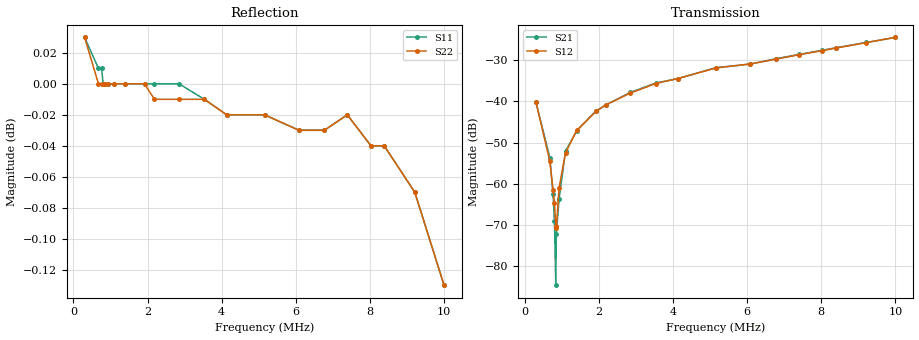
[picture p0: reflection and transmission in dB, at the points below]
!s-Parameter Generated by FASTRON Sdn. Bhd.
!FASTRON P/N : 1812AFTC-492X
!Keysight Technologies: E5071C_MY46733604_B.14.02
!Date: Wed Mar 18 14:02:51 2026
!Version  :Rev00  Wed Mar 18 14:02:51 2026
!Data & Calibration Information:
!Freq  S11:SOLT2(ON)  S21:SOLT2(ON)  S12:SOLT2(ON)  S22:SOLT2(ON)
!PortZ  Port1:50+j0  Port2:50+j0
!When reading reference impedance value at option line is always used.
! Remarks : This data is being provided solely for informational purposes.
# Hz S dB R 50
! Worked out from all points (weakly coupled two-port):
!   1601 points, 300 kHz to 10 MHz, reference 50 ohm
!   highest |S21| = -24.48 dB at 10 MHz (marker M1); lowest = -84.6 dB at 836.1 kHz (marker M2)
!   lowest |S11| = -0.1 dB at 10 MHz (marker M3), VSWR 134.99, Z = 6.41 - j202 ohm
!   |S11| at or under -10 dB: nowhere
!   |S22| runs from -0.1 to 0.0 dB; largest |S21 - S12| = 0.00071
!   S11 on the Smith chart (normalised r, x): 300 kHz: -0, +11; 2.185 MHz: 0.00, +1.36; 4.134 MHz: 0.00, +0.39; 6.088 MHz: 0.00, -0.20; 8.029 MHz: 0.00, -0.95; 10 MHz: 0.13, -4.04
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300000  0.03 10.3  -40.15 -87.6  -40.20 -89.0  0.03 -10.8
674576  0.01 22.6  -53.67 -89.8  -54.55 -87.5  0.00 -24.8
760982  0.01 25.4  -62.54 -73.5  -61.43 -85.6  0.00 -28.0
799861  0.00 26.7  -69.14 -39.8  -64.77 -47.6  0.00 -29.5
836121  0.00 27.9  -84.64 -16.4  -70.40 38.2  0.00 -30.8
850221  0.00 28.4  -72.23 70.1  -70.81 41.5  -0.00 -31.3
924755  0.00 30.8  -63.67 74.2  -60.96 84.0  -0.00 -34.1
1099099  0.00 36.6  -52.07 78.1  -52.51 85.4  -0.00 -40.6
1401155  -0.00 46.7  -47.12 85.3  -47.08 85.2  -0.00 -51.7
1917564  -0.00 63.9  -42.38 84.0  -42.46 85.2  -0.00 -70.8
2184619  -0.00 72.7  -40.89 84.3  -40.87 83.2  -0.01 -80.7
2849500  -0.00 94.8  -37.82 83.0  -38.00 83.0  -0.01 -105.3
3534704  -0.01 117.6  -35.56 81.2  -35.67 81.1  -0.01 -130.6
4133799  -0.02 137.6  -34.47 76.8  -34.46 76.8  -0.02 -152.7
5155786  -0.02 171.5  -31.82 76.4  -31.91 76.8  -0.02 169.4
6087954  -0.03 -157.3  -30.95 73.5  -30.92 73.3  -0.03 135.1
6770355  -0.03 -134.7  -29.66 73.8  -29.79 74.0  -0.03 109.8
7390266  -0.02 -114.1  -28.62 72.7  -28.70 72.9  -0.02 86.8
8028618  -0.04 -93.0  -27.61 70.8  -27.69 70.9  -0.04 63.2
8385344  -0.04 -81.2  -27.00 69.5  -27.10 69.5  -0.04 49.9
9211447  -0.07 -53.9  -25.71 65.3  -25.74 65.2  -0.07 19.2
1e7  -0.13 -27.8  -24.48 58.4  -24.47 58.4  -0.13 -10.1
